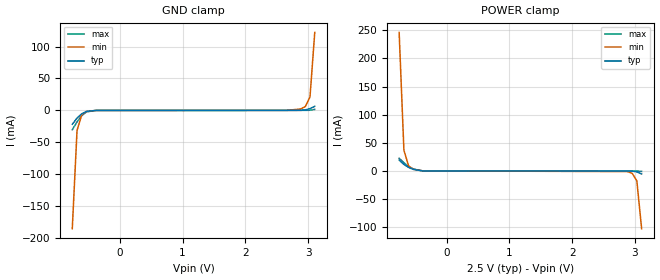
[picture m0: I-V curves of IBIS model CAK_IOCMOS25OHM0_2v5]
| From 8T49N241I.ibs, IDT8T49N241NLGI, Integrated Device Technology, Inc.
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[Model] CAK_IOCMOS25OHM0_2v5
Model_type   Input
Polarity   Non-Inverting
Vinl = 0.7V
Vinh = 1.7V
|   typ   min   max
C_comp   2pF   1.5pF   2.5pF
|   typ   min   max
[Voltage range]   2.5V   2.375V   2.625V
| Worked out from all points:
|   GND clamp passes 1 mA (typ) near -0.50 V on its own axis
|   POWER clamp passes 1 mA (typ) near -0.46 V on its own axis
[GND_clamp]
|Voltage   I (typ)   I (min)   I (max)
|Note, modeling breaks down at 250mA and above.  This is well beyond the functional   |
|operating range of the device.  Should this scenario occur, catastrophic failure and   |
|possible damage to the device and/or board is of higher concern than the I-V curve   |
|behavior.  The IBIS checker will flag currents in excess of 10A with warnings.  Lines   |
|with currents in excess of 0.35 A have been commented out.  The points still remain|
|available to the user if the user desires to use them.   |
|-2.50000e+00   -1.78512e+01   -1.44354e+01   -2.17438e+01
|-2.42424e+00   -1.70051e+01   -1.38018e+01   -2.06625e+01
|-2.34848e+00   -1.61590e+01   -1.31682e+01   -1.95813e+01
|-2.27273e+00   -1.53129e+01   -1.25347e+01   -1.85000e+01
|-2.19697e+00   -1.44670e+01   -1.19014e+01   -1.74188e+01
|-2.12121e+00   -1.36211e+01   -1.12681e+01   -1.63376e+01
|-2.04545e+00   -1.27752e+01   -1.06349e+01   -1.52565e+01
|-1.96970e+00   -1.19295e+01   -1.00019e+01   -1.41754e+01
|-1.89394e+00   -1.10838e+01   -9.36893e+00   -1.30943e+01
|-1.81818e+00   -1.02383e+01   -8.73610e+00   -1.20134e+01
|-1.74242e+00   -9.39286e+00   -8.10341e+00   -1.09325e+01
|-1.66667e+00   -8.54757e+00   -7.47086e+00   -9.85173e+00
|-1.59091e+00   -7.70243e+00   -6.83845e+00   -8.77106e+00
|-1.51515e+00   -6.85746e+00   -6.20618e+00   -7.69052e+00
|-1.43939e+00   -6.01268e+00   -5.57408e+00   -6.61012e+00
|-1.36364e+00   -5.16810e+00   -4.94214e+00   -5.52989e+00
|-1.28788e+00   -4.32375e+00   -4.31036e+00   -4.44986e+00
|-1.21212e+00   -3.47965e+00   -3.67877e+00   -3.37007e+00
|-1.13636e+00   -2.63582e+00   -3.04736e+00   -2.29054e+00
|-1.06061e+00   -1.79228e+00   -2.41617e+00   -1.21132e+00
|-9.84848e-01   -9.49059e-01   -1.78522e+00   -3.13726e-01
|-9.09091e-01   -2.87346e-01   -1.15459e+00   -6.18821e-02
|-8.33333e-01   -5.03193e-02   -5.31352e-01   -4.20123e-02
-757.6mV  -21.82mA   -185.2mA   -30.35mA
-681.8mV  -11.99mA   -31.47mA   -18.03mA
-606.1mV  -5.286mA   -6.69mA    -8.18mA
-530.3mV  -1.547mA   -1.657mA   -2.318mA
-378.8mV  -83.09uA   -102uA     -93.25uA
2.652V    3.027uA    14.99uA    610.2nA
2.879V    102.6uA    2.099mA    6.295uA
2.955V    740.5uA    5.97mA     20.38uA
3.03V     2.742mA    20.95mA    211.6uA
3.106V    6.354mA    122.1mA    1.534mA
| 3.18182e+00   1.16187e-02   6.45628e-01   4.83445e-03
| 3.25758e+00   1.93246e-02   1.50328e+00   1.01279e-02
| 3.33333e+00   4.83900e-02   2.36661e+00   1.73177e-02
| 3.40909e+00   4.24574e-01   3.23010e+00   2.52637e-02
| 3.48485e+00   1.50448e+00   4.09380e+00   3.23919e-02
| 3.56061e+00   2.65758e+00   4.95771e+00   7.78472e-02
| 3.63636e+00   3.81096e+00   5.82184e+00   8.80589e-01
| 3.71212e+00   4.96463e+00   6.68618e+00   2.35528e+00
| 3.78788e+00   6.11859e+00   7.55073e+00   3.83034e+00
| 3.86364e+00   7.27283e+00   8.41549e+00   5.30576e+00
| 3.93939e+00   8.42734e+00   9.28047e+00   6.78152e+00
| 4.01515e+00   9.58213e+00   1.01457e+01   8.25762e+00
| 4.09091e+00   1.07372e+01   1.10111e+01   9.73406e+00
| 4.16667e+00   1.18925e+01   1.18767e+01   1.12108e+01
| 4.24242e+00   1.30480e+01   1.27425e+01   1.26879e+01
| 4.31818e+00   1.42039e+01   1.36085e+01   1.41652e+01
| 4.39394e+00   1.53599e+01   1.44747e+01   1.56429e+01
| 4.46970e+00   1.65162e+01   1.53412e+01   1.71208e+01
| 4.54545e+00   1.76728e+01   1.62079e+01   1.85990e+01
| 4.62121e+00   1.88296e+01   1.70748e+01   2.00775e+01
| 4.69697e+00   1.99866e+01   1.79419e+01   2.15562e+01
| 4.77273e+00   2.11439e+01   1.88092e+01   2.30352e+01
| 4.84848e+00   2.23014e+01   1.96768e+01   2.45144e+01
| 4.92424e+00   2.34591e+01   2.05446e+01   2.59939e+01
| 5.00000e+00   2.46171e+01   2.14126e+01   2.74736e+01
[Power_clamp]
|Voltage   I (typ)   I (min)   I (max)
|Note, modeling breaks down at 250mA and above.  This is well beyond the functional   |
|operating range of the device.  Should this scenario occur, catastrophic failure and   |
|possible damage to the device and/or board is of higher concern than the I-V curve   |
|behavior.  The IBIS checker will flag currents in excess of 10A with warnings.  Lines   |
|with currents in excess of 0.35 A have been commented out.  The points still remain|
|available to the user if the user desires to use them.   |
|-2.50000e+00   2.46171e+01   1.99805e+01   2.99157e+01
|-2.42424e+00   2.34591e+01   1.91128e+01   2.84356e+01
|-2.34848e+00   2.23014e+01   1.82454e+01   2.69557e+01
|-2.27273e+00   2.11439e+01   1.73782e+01   2.54761e+01
|-2.19697e+00   1.99866e+01   1.65113e+01   2.39967e+01
|-2.12121e+00   1.88296e+01   1.56445e+01   2.25175e+01
|-2.04545e+00   1.76728e+01   1.47780e+01   2.10386e+01
|-1.96970e+00   1.65162e+01   1.39117e+01   1.95600e+01
|-1.89394e+00   1.53599e+01   1.30456e+01   1.80816e+01
|-1.81818e+00   1.42039e+01   1.21797e+01   1.66035e+01
|-1.74242e+00   1.30480e+01   1.13140e+01   1.51257e+01
|-1.66667e+00   1.18925e+01   1.04485e+01   1.36481e+01
|-1.59091e+00   1.07372e+01   9.58326e+00   1.21709e+01
|-1.51515e+00   9.58213e+00   8.71821e+00   1.06939e+01
|-1.43939e+00   8.42734e+00   7.85337e+00   9.21727e+00
|-1.36364e+00   7.27283e+00   6.98874e+00   7.74095e+00
|-1.28788e+00   6.11859e+00   6.12433e+00   6.26496e+00
|-1.21212e+00   4.96463e+00   5.26013e+00   4.78932e+00
|-1.13636e+00   3.81096e+00   4.39615e+00   3.31403e+00
|-1.06061e+00   2.65758e+00   3.53237e+00   1.83910e+00
|-9.84848e-01   1.50448e+00   2.66881e+00   4.37559e-01
|-9.09091e-01   4.24574e-01   1.80543e+00   4.63292e-02
|-8.33333e-01   4.83900e-02   9.42132e-01   2.96350e-02
-757.6mV  19.32mA    246.1mA    22.6mA
-681.8mV  11.62mA    36.79mA    14.61mA
-606.1mV  6.354mA    8.812mA    8.051mA
-530.3mV  2.742mA    3.053mA    3.449mA
-378.8mV  102.6uA    188.6uA    88.61uA
2.879V    -83.09uA   -997.3uA   -66.35uA
2.955V    -303.7uA   -4.106mA   -71.16uA
3.03V     -1.547mA   -17.66mA   -133.7uA
3.106V    -5.286mA   -102.4mA   -746.9uA
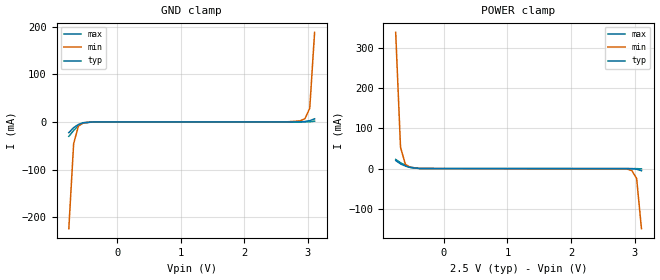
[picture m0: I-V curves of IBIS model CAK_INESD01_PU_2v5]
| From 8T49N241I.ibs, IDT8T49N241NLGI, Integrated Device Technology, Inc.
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[Model] CAK_INESD01_PU_2v5
Model_type   Input
Polarity   Non-Inverting
Vinl = 0.7V
Vinh = 1.7V
|   typ   min   max
C_comp   2pF   1.5pF   2.5pF
|   typ   min   max
[Voltage range]   2.5V   2.375V   2.625V
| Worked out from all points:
|   GND clamp passes 1 mA (typ) near -0.50 V on its own axis
|   POWER clamp passes 1 mA (typ) near -0.46 V on its own axis
[GND_clamp]
|Voltage   I (typ)   I (min)   I (max)
|Note, modeling breaks down at 250mA and above.  This is well beyond the functional   |
|operating range of the device.  Should this scenario occur, catastrophic failure and   |
|possible damage to the device and/or board is of higher concern than the I-V curve   |
|behavior.  The IBIS checker will flag currents in excess of 10A with warnings.  Lines   |
|with currents in excess of 0.35 A have been commented out.  The points still remain|
|available to the user if the user desires to use them.   |
|-2.50000e+00   -6.36025e+00   -5.17407e+00   -7.70482e+00
|-2.42424e+00   -6.07101e+00   -4.95745e+00   -7.33568e+00
|-2.34848e+00   -5.78180e+00   -4.74092e+00   -6.96655e+00
|-2.27273e+00   -5.49265e+00   -4.52447e+00   -6.59744e+00
|-2.19697e+00   -5.20356e+00   -4.30812e+00   -6.22835e+00
|-2.12121e+00   -4.91454e+00   -4.09186e+00   -5.85929e+00
|-2.04545e+00   -4.62558e+00   -3.87571e+00   -5.49028e+00
|-1.96970e+00   -4.33672e+00   -3.65966e+00   -5.12131e+00
|-1.89394e+00   -4.04795e+00   -3.44373e+00   -4.75241e+00
|-1.81818e+00   -3.75929e+00   -3.22793e+00   -4.38359e+00
|-1.74242e+00   -3.47074e+00   -3.01225e+00   -4.01485e+00
|-1.66667e+00   -3.18234e+00   -2.79671e+00   -3.64621e+00
|-1.59091e+00   -2.89408e+00   -2.58131e+00   -3.27768e+00
|-1.51515e+00   -2.60599e+00   -2.36607e+00   -2.90927e+00
|-1.43939e+00   -2.31808e+00   -2.15098e+00   -2.54101e+00
|-1.36364e+00   -2.03038e+00   -1.93605e+00   -2.17292e+00
|-1.28788e+00   -1.74291e+00   -1.72129e+00   -1.80503e+00
|-1.21212e+00   -1.45569e+00   -1.50671e+00   -1.43737e+00
|-1.13636e+00   -1.16874e+00   -1.29232e+00   -1.06998e+00
|-1.06061e+00   -8.82079e-01   -1.07814e+00   -7.02892e-01
|-9.84848e-01   -5.95739e-01   -8.64198e-01   -3.36158e-01
|-9.09091e-01   -3.09750e-01   -6.50581e-01   -6.80013e-02
|-8.33333e-01   -6.36215e-02   -4.37433e-01   -4.21899e-02
-757.6mV  -22.64mA   -224.3mA   -30.36mA
-681.8mV  -12.04mA   -45.72mA   -18.03mA
-606.1mV  -5.29mA    -8.473mA   -8.181mA
-530.3mV  -1.547mA   -1.884mA   -2.318mA
-378.8mV  -83.1uA    -105.7uA   -93.25uA
2.652V    3.027uA    15.16uA    610.2nA
2.879V    102.6uA    2.204mA    6.295uA
2.955V    740.6uA    6.867mA    20.38uA
3.03V     2.742mA    28.65mA    211.6uA
3.106V    6.357mA    188.1mA    1.534mA
| 3.18182e+00   1.16676e-02   6.21001e-01   4.83445e-03
| 3.25758e+00   2.01882e-02   1.05446e+00   1.01279e-02
| 3.33333e+00   6.36305e-02   1.48786e+00   1.73181e-02
| 3.40909e+00   4.81856e-01   1.92143e+00   2.52797e-02
| 3.48485e+00   1.06057e+00   2.35520e+00   3.30212e-02
| 3.56061e+00   1.63954e+00   2.78918e+00   1.02570e-01
| 3.63636e+00   2.21880e+00   3.22338e+00   7.53992e-01
| 3.71212e+00   2.79835e+00   3.65780e+00   1.49450e+00
| 3.78788e+00   3.37818e+00   4.09242e+00   2.23538e+00
| 3.86364e+00   3.95830e+00   4.52726e+00   2.97661e+00
| 3.93939e+00   4.53869e+00   4.96231e+00   3.71819e+00
| 4.01515e+00   5.11935e+00   5.39757e+00   4.46010e+00
| 4.09091e+00   5.70027e+00   5.83304e+00   5.20235e+00
| 4.16667e+00   6.28146e+00   6.26872e+00   5.94492e+00
| 4.24242e+00   6.86290e+00   6.70461e+00   6.68779e+00
| 4.31818e+00   7.44459e+00   7.14072e+00   7.43097e+00
| 4.39394e+00   8.02653e+00   7.57703e+00   8.17443e+00
| 4.46970e+00   8.60871e+00   8.01356e+00   8.91817e+00
| 4.54545e+00   9.19113e+00   8.45031e+00   9.66219e+00
| 4.62121e+00   9.77380e+00   8.88727e+00   1.04065e+01
| 4.69697e+00   1.03567e+01   9.32446e+00   1.11510e+01
| 4.77273e+00   1.09398e+01   9.76187e+00   1.18958e+01
| 4.84848e+00   1.15232e+01   1.01995e+01   1.26409e+01
| 4.92424e+00   1.21068e+01   1.06374e+01   1.33862e+01
| 5.00000e+00   1.26907e+01   1.10755e+01   1.41317e+01
[Power_clamp]
|Voltage   I (typ)   I (min)   I (max)
|Note, modeling breaks down at 250mA and above.  This is well beyond the functional   |
|operating range of the device.  Should this scenario occur, catastrophic failure and   |
|possible damage to the device and/or board is of higher concern than the I-V curve   |
|behavior.  The IBIS checker will flag currents in excess of 10A with warnings.  Lines   |
|with currents in excess of 0.35 A have been commented out.  The points still remain|
|available to the user if the user desires to use them.   |
|-2.50000e+00   1.26907e+01   1.03527e+01   1.53624e+01
|-2.42424e+00   1.21068e+01   9.91502e+00   1.46165e+01
|-2.34848e+00   1.15232e+01   9.47753e+00   1.38708e+01
|-2.27273e+00   1.09398e+01   9.04026e+00   1.31253e+01
|-2.19697e+00   1.03567e+01   8.60322e+00   1.23801e+01
|-2.12121e+00   9.77380e+00   8.16640e+00   1.16351e+01
|-2.04545e+00   9.19113e+00   7.72979e+00   1.08904e+01
|-1.96970e+00   8.60871e+00   7.29340e+00   1.01459e+01
|-1.89394e+00   8.02653e+00   6.85723e+00   9.40175e+00
|-1.81818e+00   7.44459e+00   6.42126e+00   8.65783e+00
|-1.74242e+00   6.86290e+00   5.98551e+00   7.91418e+00
|-1.66667e+00   6.28146e+00   5.54996e+00   7.17082e+00
|-1.59091e+00   5.70027e+00   5.11463e+00   6.42775e+00
|-1.51515e+00   5.11935e+00   4.67950e+00   5.68498e+00
|-1.43939e+00   4.53869e+00   4.24459e+00   4.94253e+00
|-1.36364e+00   3.95830e+00   3.80989e+00   4.20039e+00
|-1.28788e+00   3.37818e+00   3.37540e+00   3.45859e+00
|-1.21212e+00   2.79835e+00   2.94113e+00   2.71714e+00
|-1.13636e+00   2.21880e+00   2.50707e+00   1.97603e+00
|-1.06061e+00   1.63954e+00   2.07322e+00   1.23528e+00
|-9.84848e-01   1.06057e+00   1.63958e+00   4.94897e-01
|-9.09091e-01   4.81856e-01   1.20613e+00   5.31699e-02
|-8.33333e-01   6.36305e-02   7.72762e-01   2.98091e-02
-757.6mV  20.19mA    338.7mA    22.61mA
-681.8mV  11.67mA    53.12mA    14.61mA
-606.1mV  6.357mA    10.72mA    8.051mA
-530.3mV  2.742mA    3.275mA    3.449mA
-378.8mV  102.6uA    191.6uA    88.61uA
2.879V    -83.1uA    -1.108mA   -66.35uA
2.955V    -303.7uA   -4.97mA    -71.16uA
3.03V     -1.547mA   -24.53mA   -133.7uA
3.106V    -5.29mA    -149.4mA   -746.9uA
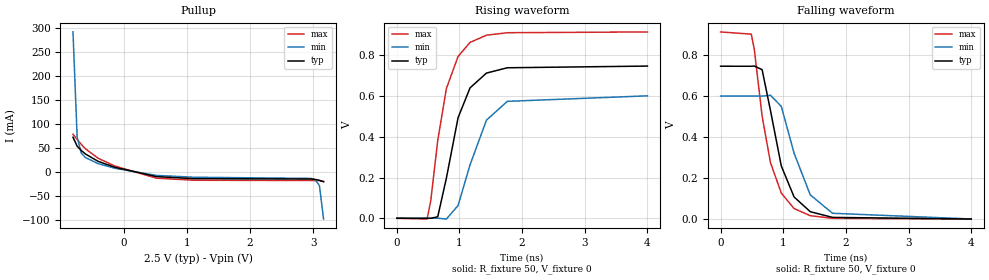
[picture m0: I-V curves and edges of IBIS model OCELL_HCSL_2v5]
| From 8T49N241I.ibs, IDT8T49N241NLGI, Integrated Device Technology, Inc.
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[Model] OCELL_HCSL_2v5
Model_type   Open_source
Polarity   Non-Inverting
|   typ   min   max
C_comp   2pF   1.5pF   2.5pF
Vmeas =0.367V
Rref = 50
Cref = 0
Vref = 0V
|   typ   min   max
[Voltage range]   2.5V   2.375V   2.625V
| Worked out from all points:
|   slope of the pullup table from 0 to 0.375 V, typ, clamps not added: 33.6 ohm
|   rising waveform, R_fixture 50, V_fixture 0: 20-80 % time 329ps typ, 390ps min, 304ps max; typ from 0 V to 0.747 V
|   falling waveform, R_fixture 50, V_fixture 0: 20-80 % time 337ps typ, 386ps min, 312ps max; typ from 0.747 V to 0 V
[Pullup]
|Voltage   I (typ)   I (min)   I (max)
|Note, modeling breaks down at 250mA and above.  This is well beyond the functional   |
|operating range of the device.  Should this scenario occur, catastrophic failure and   |
|possible damage to the device and/or board is of higher concern than the I-V curve   |
|behavior.  The IBIS checker will flag currents in excess of 10A with warnings.  Lines   |
|with currents in excess of 0.35 A have been commented out.  The points still remain|
|available to the user if the user desires to use them.   |
|-2.20000e+00   3.01970e+01   2.66683e+01   3.62360e+01
|-1.90000e+00   2.33305e+01   2.09505e+01   2.74599e+01
|-1.60000e+00   1.64682e+01   1.52370e+01   1.86865e+01
|-1.30000e+00   9.60963e+00   9.52778e+00   9.91665e+00
|-1.00000e+00   2.75507e+00   3.82254e+00   1.15348e+00
|-9.99000e-01   2.73223e+00   3.80352e+00   1.12530e+00
|-9.32920e-01   1.22304e+00   2.54732e+00   1.50761e-01
|-8.66839e-01   2.05547e-01   1.29120e+00   8.91322e-02
-800.8mV  71.88mA    291.3mA    77.93mA
-734.7mV  53.18mA    71.62mA    67.27mA
-668.6mV  44.05mA    38.44mA    56.78mA
-602.5mV  36.79mA    29.36mA    47.63mA
-404.3mV  21.63mA    16.86mA    28.13mA
-140mV    9.189mA    7.17mA     11.85mA
520.9mV   -10.24mA   -7.789mA   -13.52mA
1.116V    -14.52mA   -11.59mA   -17.86mA
2.966V    -15.29mA   -14.04mA   -18.39mA
3.032V    -16.1mA    -17.19mA   -18.44mA
3.098V    -17.95mA   -28.85mA   -18.79mA
3.164V    -20.96mA   -98.68mA   -20.15mA
| 3.23015e+00   -2.52845e-02   -5.17258e-01   -2.31281e-02
| 3.29623e+00   -3.39243e-02   -1.12724e+00   -2.76759e-02
| 3.36231e+00   -8.68158e-02   -1.73743e+00   -3.34174e-02
| 3.42839e+00   -5.43706e-01   -2.34779e+00   -3.95666e-02
| 3.49447e+00   -1.27672e+00   -2.95828e+00   -4.64283e-02
| 3.56055e+00   -2.00995e+00   -3.56888e+00   -8.01321e-02
| 3.62663e+00   -2.74340e+00   -4.17958e+00   -5.86332e-01
| 3.69271e+00   -3.47705e+00   -4.79037e+00   -1.52399e+00
| 3.75879e+00   -4.21086e+00   -5.40123e+00   -2.46177e+00
| 3.82487e+00   -4.94481e+00   -6.01218e+00   -3.39965e+00
| 3.89095e+00   -5.67888e+00   -6.62320e+00   -4.33761e+00
| 3.95703e+00   -6.41306e+00   -7.23428e+00   -5.27567e+00
| 4.02311e+00   -7.14733e+00   -7.84544e+00   -6.21387e+00
| 4.08920e+00   -7.88167e+00   -8.45666e+00   -7.15226e+00
| 4.15528e+00   -8.61609e+00   -9.06793e+00   -8.09084e+00
| 4.22136e+00   -9.35057e+00   -9.67926e+00   -9.02958e+00
| 4.28744e+00   -1.00851e+01   -1.02906e+01   -9.96845e+00
| 4.35352e+00   -1.08197e+01   -1.09021e+01   -1.09074e+01
| 4.41960e+00   -1.15543e+01   -1.15136e+01   -1.18464e+01
| 4.48568e+00   -1.22890e+01   -1.21251e+01   -1.27855e+01
| 4.55176e+00   -1.30237e+01   -1.27366e+01   -1.37246e+01
| 4.61784e+00   -1.37585e+01   -1.33482e+01   -1.46638e+01
| 4.68392e+00   -1.44933e+01   -1.39599e+01   -1.56030e+01
| 4.75000e+00   -1.52281e+01   -1.45716e+01   -1.65422e+01
| 4.75100e+00   -1.52392e+01   -1.45808e+01   -1.65564e+01
| 4.80080e+00   -1.57930e+01   -1.50418e+01   -1.72642e+01
| 4.85060e+00   -1.63469e+01   -1.55028e+01   -1.79720e+01
| 4.90040e+00   -1.69007e+01   -1.59639e+01   -1.86799e+01
| 4.95020e+00   -1.74545e+01   -1.64249e+01   -1.93877e+01
| 5.00000e+00   -1.80084e+01   -1.68860e+01   -2.00956e+01
[Ramp]
|   typ   min   max
dV/dt_r   0.452/0.33n   0.363/0.392n   0.554/0.304n
dV/dt_f   0.45/0.336n   0.363/0.387n   0.55/0.311n
R_load =   50.0000
[Rising Waveform]
R_fixture = 50
V_fixture = 0   | VCC_typ
V_fixture_max = 0   | VCC_max
V_fixture_min = 0   | VCC_min
C_fixture = 0.0p
| Time   typ   min   max
0s        1.079uV    230.9uV    3.303nV
484.4ps   10.55uV    230.3uV    -3.649mV
542.2ps   -90.6uV    229.4uV    86.22mV
653.3ps   7.217mV    243.1uV    381.6mV
791.1ps   196.2mV    -3.527mV   635.8mV
977.8ps   493.2mV    62.24mV    793.9mV
1.169ns   639.9mV    262.3mV    862.9mV
1.431ns   712.4mV    481.4mV    898.2mV
1.764ns   738.5mV    573.8mV    910.5mV
4ns       746.8mV    600.8mV    914.3mV
[Falling Waveform]
R_fixture = 50
V_fixture = 0   | VCC_typ
V_fixture_max = 0   | VCC_max
V_fixture_min = 0   | VCC_min
C_fixture = 0.0p
| Time   typ   min   max
0s        747mV      600.9mV    914.6mV
488.9ps   746.8mV    601mV      903.8mV
537.8ps   747.9mV    600.9mV    829.3mV
662.2ps   730.2mV    600.8mV    503.1mV
795.6ps   530.9mV    605.1mV    275.7mV
968.9ps   259.1mV    550.6mV    126.7mV
1.173ns   107.7mV    321.3mV    51.05mV
1.431ns   35.83mV    118mV      16.32mV
1.787ns   7.906mV    28.07mV    3.4mV
4ns       1.666uV    233.1uV    171.5nV
